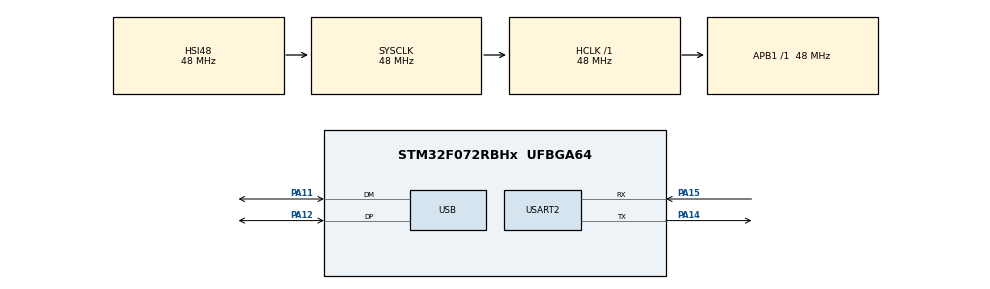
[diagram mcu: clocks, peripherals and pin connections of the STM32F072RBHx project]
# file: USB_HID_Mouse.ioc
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Mcu.Family=STM32F0
Mcu.Name=STM32F072RBHx
Mcu.Package=UFBGA64
NVIC.USB_IRQn=true\:0\:0\:false\:false\:true\:false\:true
PA11.Mode=Device
PA11.Signal=USB_DM
PA12.Mode=Device
PA12.Signal=USB_DP
PA14.Mode=Asynchronous
PA14.Signal=USART2_TX
PA15.Mode=Asynchronous
PA15.Signal=USART2_RX
ProjectManager.HeapSize=0x200
ProjectManager.StackSize=0x400
ProjectManager.TargetToolchain=MDK-ARM V5.27
RCC.AHBFreq_Value=48000000
RCC.APB1Freq_Value=48000000
RCC.APB1TimFreq_Value=48000000
RCC.HCLKFreq_Value=48000000
RCC.PLLSourceVirtual=RCC_PLLSOURCE_HSI48
RCC.SYSCLKFreq_VALUE=48000000
RCC.SYSCLKSource=RCC_SYSCLKSOURCE_HSI48
USART2.VirtualMode-Asynchronous=VM_ASYNC
USB_DEVICE.CLASS_NAME_FS=HID
USB_DEVICE.VirtualMode=Hid
USB_DEVICE.VirtualModeFS=Hid_FS
VP_USB_DEVICE_VS_USB_DEVICE_HID_FS.Mode=HID_FS
board=custom

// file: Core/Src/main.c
/* USER CODE BEGIN Header */
/**
  ******************************************************************************
  * @file           : main.c
  * @brief          : Main program body
  ******************************************************************************
  * @attention
  *
  * <h2><center>&copy; Copyright (c) 2020 STMicroelectronics.
  * All rights reserved.</center></h2>
  *
  * This software component is licensed by ST under Ultimate Liberty license
  * SLA0044, the "License"; You may not use this file except in compliance with
  * the License. You may obtain a copy of the License at:
  *                             www.st.com/SLA0044
  *
  ******************************************************************************
  */
/* USER CODE END Header */

#include "main.h"
#include "usb_device.h"
#include "user_dfu.h"
#include "user_log.h"
#include "user_hid_mouse.h"

UART_HandleTypeDef huart2;

void SystemClock_Config(void);
static void MX_GPIO_Init(void);
static void MX_USART2_UART_Init(void);

int main(void)
{
  /* USER CODE BEGIN 1 */
  IAP_Set();
  /* USER CODE END 1 */

  /* MCU Configuration--------------------------------------------------------*/

  /* Reset of all peripherals, Initializes the Flash interface and the Systick. */
  HAL_Init();

  /* Configure the system clock */
  SystemClock_Config();

  /* Initialize all configured peripherals */
  MX_GPIO_Init();
  MX_USART2_UART_Init();
  MX_USB_DEVICE_Init();
  /* USER CODE BEGIN 2 */
  pr_info("STM32F072 USB-HID Mouse");
  /* USER CODE END 2 */

  /* Infinite loop */
  while (1)
  {
    user_hid_mouse_move(10,10);
    HAL_Delay(1000);
  }
}

void SystemClock_Config(void)
{
  RCC_OscInitTypeDef RCC_OscInitStruct = {0};
  RCC_ClkInitTypeDef RCC_ClkInitStruct = {0};
  RCC_PeriphCLKInitTypeDef PeriphClkInit = {0};

  /** Initializes the CPU, AHB and APB busses clocks
  */
  RCC_OscInitStruct.OscillatorType = RCC_OSCILLATORTYPE_HSI48;
  RCC_OscInitStruct.HSI48State = RCC_HSI48_ON;
  RCC_OscInitStruct.PLL.PLLState = RCC_PLL_NONE;
  if (HAL_RCC_OscConfig(&RCC_OscInitStruct) != HAL_OK)
  {
    Error_Handler();
  }
  /** Initializes the CPU, AHB and APB busses clocks
  */
  RCC_ClkInitStruct.ClockType = RCC_CLOCKTYPE_HCLK|RCC_CLOCKTYPE_SYSCLK
                              |RCC_CLOCKTYPE_PCLK1;
  RCC_ClkInitStruct.SYSCLKSource = RCC_SYSCLKSOURCE_HSI48;
  RCC_ClkInitStruct.AHBCLKDivider = RCC_SYSCLK_DIV1;
  RCC_ClkInitStruct.APB1CLKDivider = RCC_HCLK_DIV1;

  if (HAL_RCC_ClockConfig(&RCC_ClkInitStruct, FLASH_LATENCY_1) != HAL_OK)
  {
    Error_Handler();
  }
  PeriphClkInit.PeriphClockSelection = RCC_PERIPHCLK_USB|RCC_PERIPHCLK_USART2;
  PeriphClkInit.Usart2ClockSelection = RCC_USART2CLKSOURCE_PCLK1;
  PeriphClkInit.UsbClockSelection = RCC_USBCLKSOURCE_HSI48;

  if (HAL_RCCEx_PeriphCLKConfig(&PeriphClkInit) != HAL_OK)
  {
    Error_Handler();
  }
}

static void MX_USART2_UART_Init(void)
{

  huart2.Instance = USART2;
  huart2.Init.BaudRate = 115200;
  huart2.Init.WordLength = UART_WORDLENGTH_8B;
  huart2.Init.StopBits = UART_STOPBITS_1;
  huart2.Init.Parity = UART_PARITY_NONE;
  huart2.Init.Mode = UART_MODE_TX_RX;
  huart2.Init.HwFlowCtl = UART_HWCONTROL_NONE;
  huart2.Init.OverSampling = UART_OVERSAMPLING_16;
  huart2.Init.OneBitSampling = UART_ONE_BIT_SAMPLE_DISABLE;
  huart2.AdvancedInit.AdvFeatureInit = UART_ADVFEATURE_NO_INIT;
  if (HAL_UART_Init(&huart2) != HAL_OK)
  {
    Error_Handler();
  }

}

static void MX_GPIO_Init(void)
{

  GPIO_InitTypeDef GPIO_InitStruct = {0};

  /* GPIO Ports Clock Enable */
  __HAL_RCC_GPIOB_CLK_ENABLE();
  __HAL_RCC_GPIOA_CLK_ENABLE();

  /*Configure GPIO pin Output Level */
  HAL_GPIO_WritePin(GPIOB, GPIO_PIN_9|GPIO_PIN_8, GPIO_PIN_SET);

  /*Configure GPIO pins : PB9 PB8 */
  GPIO_InitStruct.Pin = GPIO_PIN_9|GPIO_PIN_8;
  GPIO_InitStruct.Mode = GPIO_MODE_OUTPUT_PP;
  GPIO_InitStruct.Pull = GPIO_NOPULL;
  GPIO_InitStruct.Speed = GPIO_SPEED_FREQ_LOW;
  HAL_GPIO_Init(GPIOB, &GPIO_InitStruct);

}

void Error_Handler(void)
{
}

/************************ (C) COPYRIGHT STMicroelectronics *****END OF FILE****/
